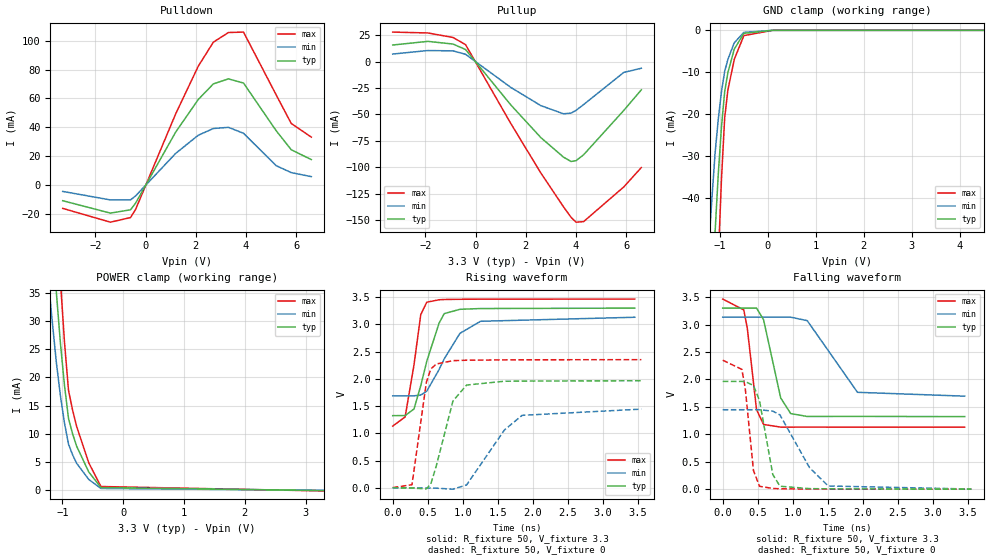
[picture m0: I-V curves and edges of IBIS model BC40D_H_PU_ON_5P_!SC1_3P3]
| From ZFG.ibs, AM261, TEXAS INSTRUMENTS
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[Model]   BC40D_H_PU_ON_5P_!SC1_3P3
Model_type   I/O
Polarity   Non-Inverting
Enable   Active-Low
Vinl =  0.8V
Vinh =  2V
Cref =  15pF
Rref =  100.0000M
Vref =  0V
Vmeas =  1.65
C_comp   2.157014p   1.964007p   2.198404p
|[Input load] weak_pu_on
|[Output drive] fast
|[supplytol] 5
|[temp] ind
[Model Spec]
Vinl   0.8V   0.8V   0.8V
Vinh   2V   2V   2V
[Temperature Range]   25   125   -40
[Voltage Range]   3.3   3.135   3.465
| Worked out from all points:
|   slope of the pulldown table from 0 to 0.495 V, typ, clamps not added: 31.8 ohm
|   slope of the pullup table from 0 to 0.495 V, typ, clamps not added: 33.3 ohm
|   GND clamp passes 1 mA (typ) near -0.52 V on its own axis
|   POWER clamp passes 1 mA (typ) near -0.43 V on its own axis
|   rising waveform, R_fixture 50, V_fixture 3.3: 20-80 % time 258ps typ, 377ps min, 156ps max; typ from 1.32 V to 3.3 V
|   rising waveform, R_fixture 50, V_fixture 0: 20-80 % time 233ps typ, 458ps min, 142ps max; typ from 0 V to 1.97 V
|   falling waveform, R_fixture 50, V_fixture 3.3: 20-80 % time 199ps typ, 410ps min, 121ps max; typ from 3.3 V to 1.32 V
|   falling waveform, R_fixture 50, V_fixture 0: 20-80 % time 162ps typ, 365ps min, 108ps max; typ from 1.96 V to 0.003 V
| Nom Voltages:
|   VDD=1.1, VDDS=3.3, VDDS18=1.8, ESD_BIASFET=0, VSS=0, VSSS=0
| Min Voltages:
|   VDD=1.045, VDDS=3.135, VDDS18=1.71, ESD_BIASFET=0, VSS=0, VSSS=0
| Max Voltages:
|   VDD=1.16, VDDS=3.465, VDDS18=1.89, ESD_BIASFET=0, VSS=0, VSSS=0
[POWER_clamp]
|   voltage   I(typ)   I(min)   I(max)
-3.3V     446.9mA    437.1mA    604mA
-1.233V   56.55mA    37.5mA     80.28mA
-1.167V   45.63mA    29.89mA    65.07mA
-1.1V     35.1mA     22.65mA    50.26mA
-1.033V   26.08mA    16.75mA    37.2mA
-966.7mV  18.62mA    11.92mA    26.34mA
-900mV    12.7mA     8.144mA    17.7mA
-833.3mV  10mA       6.261mA    14.22mA
-766.7mV  7.795mA    4.75mA     11.31mA
-566.7mV  3.199mA    1.871mA    4.824mA
-366.7mV  433.5uA    268.9uA    617.1uA
3.3V      -100.3uA   -54.66uA   -173.1uA
[Pulldown]
|   voltage   I(typ)   I(min)   I(max)
-3.3V     -10.92mA   -4.469mA   -16.24mA
-1.4V     -19.52mA   -10.37mA   -25.81mA
-600mV    -17.22mA   -10.34mA   -22.6mA
-400mV    -12.67mA   -7.623mA   -17.05mA
1.2V      36.7mA     21.92mA    49.35mA
2.1V      59.3mA     34.49mA    82.4mA
2.7V      70.09mA    39.15mA    99.03mA
3.3V      73.56mA    39.95mA    105.7mA
3.9V      70.66mA    35.84mA    106mA
5.2V      37.64mA    13.39mA    62.46mA
5.8V      24.43mA    8.578mA    42.66mA
6.6V      17.6mA     5.765mA    33.17mA
[Pullup]
|   voltage   I(typ)   I(min)   I(max)
-3.3V     15.77mA    7.22mA     28.03mA
-1.9V     19.23mA    10.53mA    27.2mA
-900mV    16.69mA    10.25mA    22.94mA
-400mV    11.53mA    6.969mA    16.15mA
1.4V      -40.96mA   -24.37mA   -58.54mA
2.6V      -72.01mA   -41.71mA   -105.6mA
3.5V      -90.51mA   -49.41mA   -137.6mA
3.8V      -94.64mA   -48.83mA   -147.5mA
4V        -93.89mA   -46.21mA   -152.2mA
4.3V      -88.33mA   -40.72mA   -151.7mA
5.9V      -46.29mA   -10.2mA    -118.8mA
6.6V      -26.71mA   -6.269mA   -100.4mA
[GND_clamp]
|   voltage   I(typ)   I(min)   I(max)
-3.3V     -787.2mA   -627.7mA   -1.235A
-1.233V   -85.67mA   -52.14mA   -138.8mA
-1.167V   -66.48mA   -40.37mA   -107.8mA
-1.1V     -48.26mA   -29.38mA   -78.01mA
-1.033V   -34.3mA    -21.2mA    -54.61mA
-966.7mV  -23.1mA    -14.68mA   -35.59mA
-900mV    -14.66mA   -9.807mA   -20.94mA
-833.3mV  -10.12mA   -6.96mA    -14.29mA
-700mV    -4.501mA   -2.971mA   -6.963mA
-500mV    -717.7uA   -493.4uA   -1.261mA
100mV     0A         0A         0A
6.6V      0A         0A         0A
[Ramp]
| variable   typ   min   max
dV/dt_f  1.1950009/0.20080853n 0.88975764/0.42406791n  1.4061698/0.12174193n
dV/dt_r  1.1920104/0.23568046n 0.88882206/0.46966013n  1.4196578/0.14317133n
R_load = 50
[Rising Waveform]
R_fixture = 50
V_fixture = 3.3
V_fixture_min = 3.135
V_fixture_max = 3.465
|   time   V(typ)   V(min)   V(max)
0s        1.324V     1.688V     1.132V
177.2ps   1.325V     1.688V     1.301V
303.7ps   1.447V     1.688V     2.256V
400.3ps   1.875V     1.703V     3.18V
485.8ps   2.322V     1.773V     3.407V
661.9ps   3.024V     2.171V     3.452V
735.5ps   3.198V     2.369V     3.457V
959.3ps   3.277V     2.836V     3.461V
1.253ns   3.291V     3.057V     3.463V
3.453ns   3.299V     3.131V     3.465V
[Rising Waveform]
R_fixture = 50
V_fixture = 0
V_fixture_min = 0
V_fixture_max = 0
|   time   V(typ)   V(min)   V(max)
0s        0V         0V         3.507mV
274.9ps   -4.733mV   0V         55.55mV
480.1ps   -20.97mV   -3.534mV   1.937V
543.7ps   69.38mV    -5.301mV   2.181V
622.4ps   404.7mV    -7.595mV   2.273V
859ps     1.592V     -25.75mV   2.334V
1.054ns   1.886V     51.53mV    2.342V
1.594ns   1.956V     1.061V     2.348V
1.846ns   1.959V     1.33V      2.35V
3.547ns   1.965V     1.444V     2.352V
[Falling Waveform]
R_fixture = 50
V_fixture = 3.3
V_fixture_min = 3.135
V_fixture_max = 3.465
|   time   V(typ)   V(min)   V(max)
0s        3.3V       3.134V     3.464V
301ps     3.3V       3.134V     3.266V
351.3ps   3.3V       3.134V     2.93V
482.7ps   3.3V       3.134V     1.45V
582.8ps   3.088V     3.134V     1.181V
827.6ps   1.663V     3.134V     1.132V
969.8ps   1.379V     3.134V     1.132V
1.206ns   1.326V     3.071V     1.133V
1.923ns   1.327V     1.766V     1.131V
3.453ns   1.324V     1.696V     1.131V
[Falling Waveform]
R_fixture = 50
V_fixture = 0
V_fixture_min = 0
V_fixture_max = 0
|   time   V(typ)   V(min)   V(max)
0s        1.964V     1.449V     2.351V
273.2ps   1.964V     1.449V     2.184V
322.1ps   1.961V     1.449V     1.833V
438.5ps   1.891V     1.449V     343.6mV
525.2ps   1.614V     1.449V     54.57mV
714.7ps   268.2mV    1.423V     15.15mV
817.3ps   55.88mV    1.353V     9.958mV
1.24ns    12.36mV    391.8mV    4.301mV
1.506ns   8.553mV    60.15mV    3.207mV
3.547ns   2.504mV    4.605mV    2.797mV
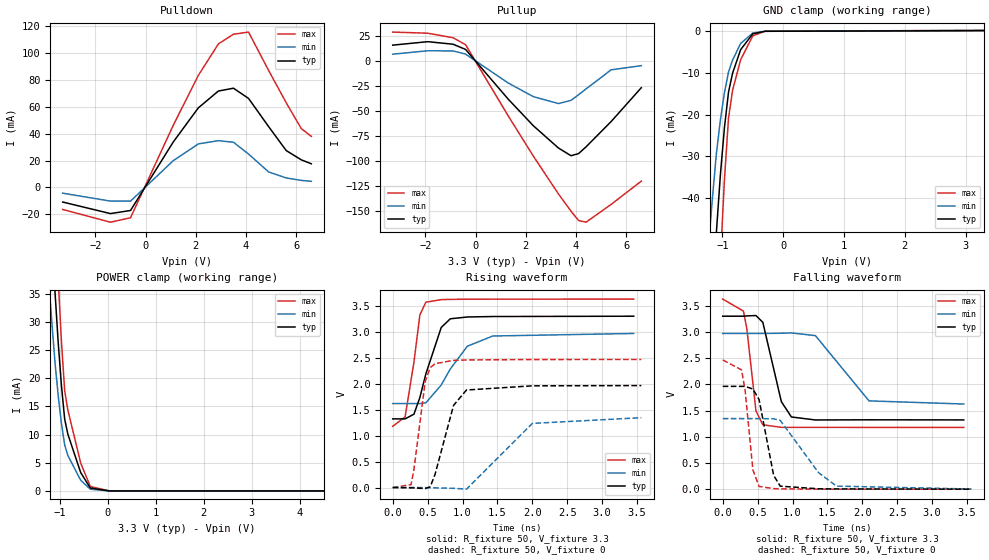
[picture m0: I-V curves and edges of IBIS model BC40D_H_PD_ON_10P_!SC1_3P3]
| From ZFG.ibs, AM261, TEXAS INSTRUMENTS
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[Model]   BC40D_H_PD_ON_10P_!SC1_3P3
Model_type   I/O
Polarity   Non-Inverting
Enable   Active-Low
Vinl =  0.8V
Vinh =  2V
Cref =  15pF
Rref =  100.0000M
Vref =  0V
Vmeas =  1.65
C_comp   2.157014p   1.997104p   2.250886p
|[Input load] weak_pd_on
|[Output drive] fast
|[supplytol] 10
|[temp] ind
[Model Spec]
Vinl   0.8V   0.8V   0.8V
Vinh   2V   2V   2V
[Temperature Range]   25   125   -40
[Voltage Range]   3.3   2.97   3.63
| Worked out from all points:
|   slope of the pulldown table from 0 to 0.495 V, typ, clamps not added: 31.8 ohm
|   slope of the pullup table from 0 to 0.495 V, typ, clamps not added: 33.3 ohm
|   GND clamp passes 1 mA (typ) near -0.52 V on its own axis
|   POWER clamp passes 1 mA (typ) near -0.42 V on its own axis
|   rising waveform, R_fixture 50, V_fixture 3.3: 20-80 % time 258ps typ, 391ps min, 146ps max; typ from 1.32 V to 3.3 V
|   rising waveform, R_fixture 50, V_fixture 0: 20-80 % time 233ps typ, 479ps min, 138ps max; typ from 0 V to 1.96 V
|   falling waveform, R_fixture 50, V_fixture 3.3: 20-80 % time 199ps typ, 427ps min, 119ps max; typ from 3.3 V to 1.32 V
|   falling waveform, R_fixture 50, V_fixture 0: 20-80 % time 162ps typ, 386ps min, 107ps max; typ from 1.96 V to 0 V
| Nom Voltages:
|   VDD=1.1001, VDDS=3.3, VDDS18=1.8, ESD_BIASFET=0, VSS=0, VSSS=0
| Min Voltages:
|   VDD=0.99, VDDS=2.97, VDDS18=1.62, ESD_BIASFET=0, VSS=0, VSSS=0
| Max Voltages:
|   VDD=1.21, VDDS=3.63, VDDS18=1.98, ESD_BIASFET=0, VSS=0, VSSS=0
[POWER_clamp]
|   voltage   I(typ)   I(min)   I(max)
-3.3V     446.9mA    419.5mA    603.9mA
-1.233V   56.59mA    37.53mA    80.37mA
-1.167V   45.68mA    29.91mA    65.17mA
-1.1V     35.14mA    22.68mA    50.36mA
-1.033V   26.13mA    16.78mA    37.31mA
-966.7mV  18.67mA    11.95mA    26.46mA
-900mV    12.76mA    8.172mA    17.82mA
-833.3mV  10.07mA    6.29mA     14.35mA
-566.7mV  3.276mA    1.904mA    4.983mA
-366.7mV  519.9uA    307.2uA    792.3uA
33.33mV   0A         0A         0A
6.6V      0A         0A         0A
[Pulldown]
|   voltage   I(typ)   I(min)   I(max)
-3.3V     -10.92mA   -4.307mA   -16.45mA
-1.4V     -19.52mA   -10.22mA   -25.94mA
-600mV    -17.22mA   -10.25mA   -22.66mA
1.1V      33.8mA     19.88mA    46.22mA
2.1V      59.3mA     32.44mA    83.48mA
2.9V      71.86mA    34.84mA    107mA
3.5V      73.95mA    33.66mA    114.2mA
4.1V      66.34mA    24.89mA    115.8mA
4.9V      45.33mA    11.53mA    87.2mA
5.6V      27.47mA    7.046mA    63.1mA
6.2V      20.56mA    5.221mA    43.87mA
6.6V      17.6mA     4.555mA    38.05mA
[Pullup]
|   voltage   I(typ)   I(min)   I(max)
-3.3V     15.77mA    6.741mA    28.8mA
-1.9V     19.23mA    10.15mA    27.67mA
-900mV    16.69mA    10.02mA    23.17mA
-400mV    11.53mA    6.853mA    16.25mA
1.3V      -38.16mA   -22.04mA   -54.89mA
2.3V      -64.7mA    -35.66mA   -95.04mA
3.3V      -86.93mA   -42.57mA   -132.8mA
3.8V      -94.64mA   -39.36mA   -150mA
4.1V      -92.53mA   -33.79mA   -159.3mA
4.4V      -85.77mA   -27.94mA   -161mA
5.4V      -60.46mA   -8.849mA   -143.2mA
6.6V      -26.71mA   -4.741mA   -120mA
[GND_clamp]
|   voltage   I(typ)   I(min)   I(max)
-3.3V     -787.2mA   -607.8mA   -1.235A
-1.233V   -85.66mA   -52.14mA   -138.8mA
-1.167V   -66.47mA   -40.37mA   -107.7mA
-1.1V     -48.25mA   -29.37mA   -77.99mA
-1.033V   -34.28mA   -21.19mA   -54.56mA
-966.7mV  -23.07mA   -14.67mA   -35.51mA
-900mV    -14.62mA   -9.792mA   -20.84mA
-833.3mV  -10.07mA   -6.938mA   -14.17mA
-700mV    -4.435mA   -2.939mA   -6.836mA
-500mV    -641.2uA   -454.5uA   -1.12mA
-300mV    -31.62uA   -32.73uA   -44.27uA
3.3V      108.6uA    159.4uA    198.5uA
[Ramp]
| variable   typ   min   max
dV/dt_f  1.1954816/0.20074978n 0.83576296/0.44363752n  1.4751037/0.11965581n
dV/dt_r  1.1916349/0.23568191n 0.82814892/0.49061137n  1.4892937/0.13872759n
R_load = 50
[Rising Waveform]
R_fixture = 50
V_fixture = 3.3
V_fixture_min = 2.97
V_fixture_max = 3.63
|   time   V(typ)   V(min)   V(max)
0s        1.321V     1.616V     1.179V
177.6ps   1.321V     1.616V     1.358V
303.9ps   1.411V     1.616V     2.409V
389.3ps   1.733V     1.616V     3.322V
475.1ps   2.187V     1.631V     3.566V
695.1ps   3.08V      1.973V     3.616V
824.7ps   3.247V     2.281V     3.621V
1.069ns   3.282V     2.719V     3.624V
1.434ns   3.291V     2.916V     3.625V
3.453ns   3.297V     2.965V     3.627V
[Rising Waveform]
R_fixture = 50
V_fixture = 0
V_fixture_min = 0
V_fixture_max = 0
|   time   V(typ)   V(min)   V(max)
0s        0V         0V         0V
263ps     -5.429mV   0V         55.93mV
302.5ps   -7.292mV   0V         330.3mV
465.3ps   -20.65mV   -2.403mV   2.039V
538ps     15.37mV    -3.759mV   2.309V
607.8ps   257.9mV    -5.571mV   2.384V
871.4ps   1.58V      -15.22mV   2.447V
1.057ns   1.877V     -31.71mV   2.455V
2.001ns   1.957V     1.234V     2.463V
3.562ns   1.962V     1.344V     2.465V
[Falling Waveform]
R_fixture = 50
V_fixture = 3.3
V_fixture_min = 2.97
V_fixture_max = 3.63
|   time   V(typ)   V(min)   V(max)
0s        3.299V     2.97V      3.626V
296.4ps   3.299V     2.97V      3.397V
344.8ps   3.305V     2.97V      3.071V
476.3ps   3.312V     2.97V      1.493V
574.8ps   3.182V     2.97V      1.228V
840.1ps   1.67V      2.974V     1.179V
984ps     1.377V     2.98V      1.179V
1.328ns   1.32V      2.929V     1.179V
2.096ns   1.323V     1.684V     1.178V
3.453ns   1.321V     1.624V     1.178V
[Falling Waveform]
R_fixture = 50
V_fixture = 0
V_fixture_min = 0
V_fixture_max = 0
|   time   V(typ)   V(min)   V(max)
0s        1.961V     1.346V     2.465V
269.2ps   1.961V     1.346V     2.276V
320ps     1.96V      1.346V     1.899V
432.6ps   1.911V     1.346V     366.2mV
521.1ps   1.709V     1.346V     52.16mV
729.8ps   262.9mV    1.343V     10.73mV
824.7ps   56.8mV     1.312V     6.105mV
1.374ns   6.947mV    314mV      0V
1.63ns    4.837mV    58.06mV    0V
3.562ns   0V         2.766mV    0V
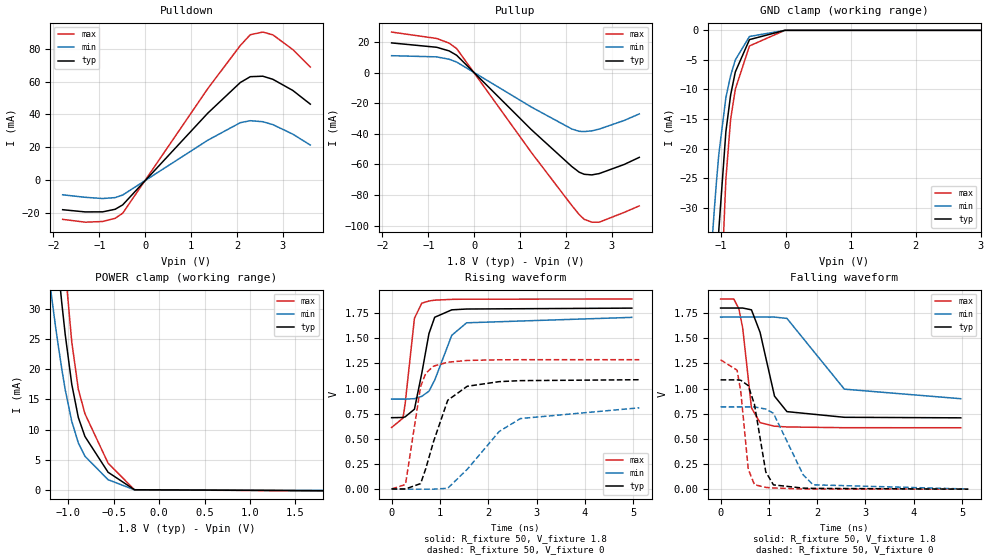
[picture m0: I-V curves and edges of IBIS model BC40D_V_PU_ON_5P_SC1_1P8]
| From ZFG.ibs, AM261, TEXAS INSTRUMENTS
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[Model]   BC40D_V_PU_ON_5P_SC1_1P8
Model_type   I/O
Polarity   Non-Inverting
Enable   Active-Low
Vinl =  0.63
Vinh =  1.17
Cref =  15pF
Rref =  100.0000M
Vref =  0V
Vmeas =  0.9
C_comp   2.233931p   2.204415p   2.290246p
|[Input load] weak_pu_on
|[Output drive] slow
|[supplytol] 5
|[temp] ind
[Model Spec]
Vinl   0.63   0.5985   0.6615
Vinh   1.17   1.1115   1.2285
[Temperature Range]   25   125   -40
[Voltage Range]   1.8   1.71   1.89
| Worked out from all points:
|   slope of the pulldown table from 0 to 0.27 V, typ, clamps not added: 32.2 ohm
|   slope of the pullup table from 0 to 0.27 V, typ, clamps not added: 32.6 ohm
|   GND clamp passes 1 mA (typ) near -0.52 V on its own axis
|   POWER clamp passes 1 mA (typ) near -0.44 V on its own axis
|   rising waveform, R_fixture 50, V_fixture 1.8: 20-80 % time 245ps typ, 395ps min, 168ps max; typ from 0.711 V to 1.8 V
|   rising waveform, R_fixture 50, V_fixture 0: 20-80 % time 428ps typ, 921ps min, 245ps max; typ from 0.002 V to 1.09 V
|   falling waveform, R_fixture 50, V_fixture 1.8: 20-80 % time 308ps typ, 718ps min, 171ps max; typ from 1.8 V to 0.71 V
|   falling waveform, R_fixture 50, V_fixture 0: 20-80 % time 226ps typ, 430ps min, 154ps max; typ from 1.09 V to 0.002 V
| Nom Voltages:
|   VDD=1.1, VDDS=1.8, VDDS18=1.8, ESD_BIASFET=0, VSS=0, VSSS=0
| Min Voltages:
|   VDD=1.045, VDDS=1.71, VDDS18=1.71, ESD_BIASFET=0, VSS=0, VSSS=0
| Max Voltages:
|   VDD=1.16, VDDS=1.89, VDDS18=1.89, ESD_BIASFET=0, VSS=0, VSSS=0
[POWER_clamp]
|   voltage   I(typ)   I(min)   I(max)
-1.8V     158.8mA    112.5mA    219.8mA
-1.255V   59.97mA    40.01mA    84.91mA
-1.145V   41.92mA    27.41mA    59.76mA
-1.109V   36.32mA    23.62mA    51.83mA
-1.073V   30.96mA    20.04mA    44.16mA
-1.036V   25.83mA    16.67mA    36.76mA
-963.6mV  17.54mA    11.39mA    24.56mA
-890.9mV  12.01mA    7.798mA    16.67mA
-818.2mV  8.875mA    5.598mA    12.64mA
-563.6mV  2.954mA    1.726mA    4.46mA
-272.7mV  55.97uA    39.54uA    57.56uA
1.8V      -99.94uA   -59.14uA   -145.1uA
[Pulldown]
|   voltage   I(typ)   I(min)   I(max)
-1.8V     -17.92mA   -8.85mA    -23.8mA
-1.309V   -19.26mA   -10.37mA   -25.51mA
-927.3mV  -19.22mA   -11.12mA   -25.08mA
-654.5mV  -17.65mA   -10.56mA   -23.13mA
-490.9mV  -14.97mA   -8.985mA   -20.05mA
1.364V    40.78mA    24.32mA    55.7mA
2.073V    59.4mA     35mA       81.9mA
2.291V    62.96mA    36.2mA     88.48mA
2.564V    63.25mA    35.58mA    90.07mA
2.782V    61.38mA    33.82mA    88.42mA
3.218V    54.59mA    28.02mA    79.45mA
3.6V      46.26mA    21.39mA    68.79mA
[Pullup]
-1.8V     19.42mA    11.07mA    26.5mA
-818.2mV  16.58mA    10.3mA     22.34mA
-545.5mV  14.19mA    8.748mA    19.29mA
-381.8mV  11.34mA    6.915mA    15.7mA
1.255V    -37.51mA   -22.64mA   -52.53mA
2.127V    -61.34mA   -36.82mA   -86.78mA
2.291V    -65.12mA   -38.38mA   -92.82mA
2.4V      -66.46mA   -38.53mA   -95.91mA
2.564V    -66.86mA   -38.08mA   -97.75mA
2.727V    -65.99mA   -36.9mA    -97.78mA
3.273V    -60.01mA   -31.26mA   -91.34mA
3.6V      -55.4mA    -26.98mA   -87.12mA
[GND_clamp]
|   voltage   I(typ)   I(min)   I(max)
-1.8V     -270.2mA   -170.2mA   -430.1mA
-1.255V   -91.68mA   -55.92mA   -148.5mA
-1.145V   -59.94mA   -36.46mA   -97.14mA
-1.109V   -50.51mA   -30.84mA   -81.61mA
-1.073V   -41.77mA   -25.67mA   -67.13mA
-1.036V   -33.71mA   -20.95mA   -53.68mA
-927.3mV  -17.15mA   -11.38mA   -25.19mA
-854.5mV  -10.96mA   -7.663mA   -15.08mA
-781.8mV  -7.031mA   -5.001mA   -9.947mA
-563.6mV  -1.569mA   -1.041mA   -2.641mA
-18.18mV  0A         0A         0A
3.6V      0A         0A         0A
[Ramp]
| variable   typ   min   max
dV/dt_f 0.66095896/0.3106084n 0.49613312/0.73326127n 0.77259659/0.17250259n
dV/dt_r 0.65862655/0.43190461n 0.50230725/0.96092972n 0.77696157/0.24571965n
R_load = 50
[Rising Waveform]
R_fixture = 50
V_fixture = 1.8
V_fixture_min = 1.71
V_fixture_max = 1.89
|   time   V(typ)   V(min)   V(max)
0s        710.6mV    895.2mV    613.1mV
234.7ps   712.8mV    895.2mV    706mV
279.7ps   718.7mV    895.2mV    848.3mV
472.8ps   795.2mV    899.6mV    1.7V
625.3ps   1.154V     923mV      1.849V
773.2ps   1.547V     974.1mV    1.871V
891.9ps   1.709V     1.084V     1.879V
1.246ns   1.783V     1.53V      1.887V
1.553ns   1.791V     1.654V     1.889V
4.974ns   1.8V       1.708V     1.89V
[Rising Waveform]
R_fixture = 50
V_fixture = 0
V_fixture_min = 0
V_fixture_max = 0
|   time   V(typ)   V(min)   V(max)
0s        2.021mV    0V         2.349mV
286.7ps   2.021mV    0V         46.67mV
600.6ps   55.49mV    0V         1.02V
705.3ps   201.5mV    0V         1.151V
868.1ps   473.5mV    0V         1.223V
1.162ns   884.2mV    8.941mV    1.262V
1.566ns   1.023V     197.8mV    1.28V
2.228ns   1.069V     573.6mV    1.286V
2.667ns   1.079V     702.1mV    1.287V
5.128ns   1.088V     808.9mV    1.287V
[Falling Waveform]
R_fixture = 50
V_fixture = 1.8
V_fixture_min = 1.71
V_fixture_max = 1.89
|   time   V(typ)   V(min)   V(max)
0s        1.8V       1.71V      1.889V
275ps     1.8V       1.71V      1.889V
378.3ps   1.8V       1.71V      1.793V
458.3ps   1.8V       1.71V      1.601V
639.6ps   1.782V     1.71V      809mV
817.4ps   1.559V     1.71V      662.6mV
1.117ns   924.9mV    1.71V      627.2mV
1.374ns   771.8mV    1.697V     619.7mV
2.563ns   715.4mV    994.7mV    612.1mV
4.974ns   710.1mV    900mV      611.7mV
[Falling Waveform]
R_fixture = 50
V_fixture = 0
V_fixture_min = 0
V_fixture_max = 0
|   time   V(typ)   V(min)   V(max)
0s        1.087V     818.9mV    1.286V
342.4ps   1.087V     818.9mV    1.183V
418.5ps   1.083V     818.9mV    970.8mV
572.8ps   1.03V      818.9mV    201.5mV
701.2ps   844.1mV    818.9mV    46.7mV
936.2ps   172.9mV    797.1mV    19.49mV
1.095ns   44.58mV    755.1mV    13.55mV
1.708ns   12.56mV    145.8mV    3.939mV
1.914ns   10.01mV    45.38mV    3.232mV
5.128ns   2.074mV    3.413mV    2.43mV
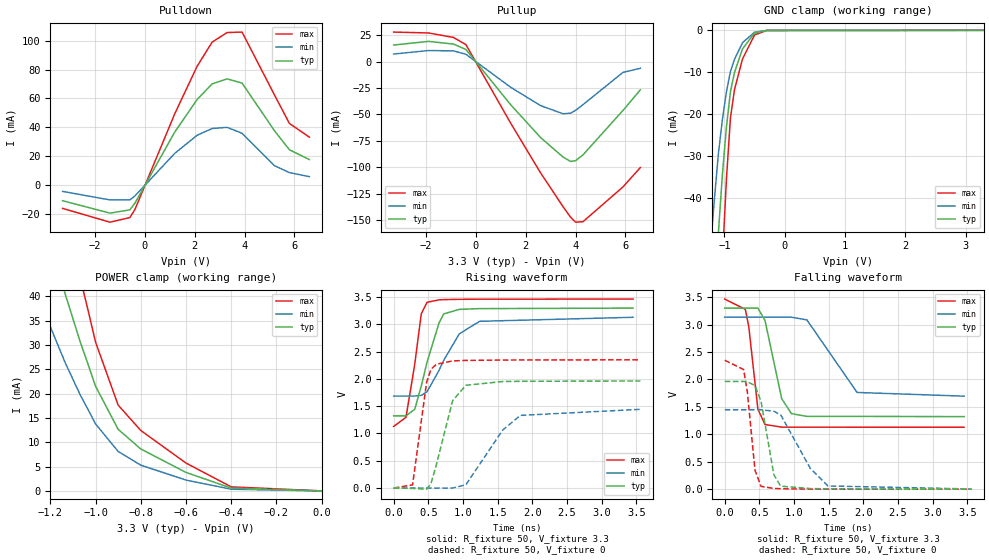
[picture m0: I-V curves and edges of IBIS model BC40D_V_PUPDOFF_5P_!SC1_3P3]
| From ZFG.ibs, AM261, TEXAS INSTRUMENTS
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[Model]   BC40D_V_PUPDOFF_5P_!SC1_3P3
Model_type   I/O
Polarity   Non-Inverting
Enable   Active-Low
Vinl =  0.8V
Vinh =  2V
Cref =  15pF
Rref =  100.0000M
Vref =  0V
Vmeas =  1.65
C_comp   2.059994p   1.862014p   2.067327p
|[Input load] weak_pupdoff
|[Output drive] fast
|[supplytol] 5
|[temp] ind
[Model Spec]
Vinl   0.8V   0.8V   0.8V
Vinh   2V   2V   2V
[Temperature Range]   25   125   -40
[Voltage Range]   3.3   3.135   3.465
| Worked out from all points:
|   slope of the pulldown table from 0 to 0.495 V, typ, clamps not added: 31.8 ohm
|   slope of the pullup table from 0 to 0.495 V, typ, clamps not added: 33.3 ohm
|   GND clamp passes 1 mA (typ) near -0.53 V on its own axis
|   POWER clamp passes 1 mA (typ) near -0.43 V on its own axis
|   rising waveform, R_fixture 50, V_fixture 3.3: 20-80 % time 251ps typ, 371ps min, 151ps max; typ from 1.32 V to 3.3 V
|   rising waveform, R_fixture 50, V_fixture 0: 20-80 % time 232ps typ, 456ps min, 141ps max; typ from 0 V to 1.96 V
|   falling waveform, R_fixture 50, V_fixture 3.3: 20-80 % time 196ps typ, 407ps min, 120ps max; typ from 3.3 V to 1.32 V
|   falling waveform, R_fixture 50, V_fixture 0: 20-80 % time 159ps typ, 360ps min, 107ps max; typ from 1.96 V to 0 V
| Nom Voltages:
|   VDD=1.1, VDDS=3.3, VDDS18=1.8, ESD_BIASFET=0, VSS=0, VSSS=0
| Min Voltages:
|   VDD=1.045, VDDS=3.135, VDDS18=1.71, ESD_BIASFET=0, VSS=0, VSSS=0
| Max Voltages:
|   VDD=1.16, VDDS=3.465, VDDS18=1.89, ESD_BIASFET=0, VSS=0, VSSS=0
[POWER_clamp]
|   voltage   I(typ)   I(min)   I(max)
-3.3V     446.9mA    437.1mA    604mA
-1.267V   62.17mA    41.49mA    88.04mA
-1.233V   56.52mA    37.49mA    80.24mA
-1.133V   40.34mA    26.26mA    57.63mA
-1.067V   30.56mA    19.69mA    43.69mA
-1.033V   26.05mA    16.74mA    37.16mA
-1V       21.55mA    13.79mA    30.63mA
-900mV    12.68mA    8.13mA     17.66mA
-800mV    8.63mA     5.305mA    12.44mA
-600mV    3.813mA    2.231mA    5.735mA
-400mV    580.7uA    357.4uA    841.8uA
0V        4.589uA    2.331uA    8.159uA
[Pulldown]
|   voltage   I(typ)   I(min)   I(max)
-3.3V     -10.92mA   -4.469mA   -16.24mA
-1.4V     -19.52mA   -10.37mA   -25.81mA
-600mV    -17.22mA   -10.34mA   -22.6mA
-400mV    -12.67mA   -7.623mA   -17.05mA
1.2V      36.7mA     21.92mA    49.35mA
2.1V      59.3mA     34.49mA    82.4mA
2.7V      70.09mA    39.15mA    99.03mA
3.3V      73.56mA    39.95mA    105.7mA
3.9V      70.66mA    35.84mA    106mA
5.2V      37.64mA    13.39mA    62.46mA
5.8V      24.43mA    8.578mA    42.66mA
6.6V      17.6mA     5.765mA    33.17mA
[Pullup]
|   voltage   I(typ)   I(min)   I(max)
-3.3V     15.77mA    7.22mA     28.03mA
-1.9V     19.23mA    10.53mA    27.2mA
-900mV    16.69mA    10.25mA    22.94mA
-400mV    11.53mA    6.969mA    16.15mA
1.4V      -40.96mA   -24.37mA   -58.54mA
2.6V      -72.01mA   -41.71mA   -105.6mA
3.5V      -90.51mA   -49.41mA   -137.6mA
3.8V      -94.64mA   -48.83mA   -147.5mA
4V        -93.88mA   -46.2mA    -152.2mA
4.3V      -88.33mA   -40.72mA   -151.7mA
5.9V      -46.29mA   -10.2mA    -118.8mA
6.6V      -26.71mA   -6.269mA   -100.4mA
[GND_clamp]
|   voltage   I(typ)   I(min)   I(max)
-3.3V     -787.2mA   -627.7mA   -1.235A
-1.233V   -85.66mA   -52.14mA   -138.8mA
-1.167V   -66.47mA   -40.37mA   -107.7mA
-1.1V     -48.25mA   -29.37mA   -77.98mA
-1.033V   -34.27mA   -21.19mA   -54.56mA
-966.7mV  -23.06mA   -14.66mA   -35.5mA
-900mV    -14.61mA   -9.789mA   -20.83mA
-833.3mV  -10.05mA   -6.934mA   -14.15mA
-700mV    -4.416mA   -2.931mA   -6.81mA
-500mV    -621.6uA   -443.6uA   -1.094mA
-300mV    -17.13uA   -24.35uA   -23.51uA
3.3V      4.589uA    5.188uA    6.318uA
[Ramp]
| variable   typ   min   max
dV/dt_f  1.1959432/0.19778326n 0.88997478/0.42010629n  1.4076426/0.12045204n
dV/dt_r  1.1917501/0.23458044n 0.88925157/0.46804062n  1.4206668/0.14157829n
R_load = 50
[Rising Waveform]
R_fixture = 50
V_fixture = 3.3
V_fixture_min = 3.135
V_fixture_max = 3.465
|   time   V(typ)   V(min)   V(max)
0s        1.323V     1.687V     1.129V
178.2ps   1.324V     1.687V     1.297V
304.7ps   1.446V     1.687V     2.276V
398.7ps   1.871V     1.7V       3.195V
481.7ps   2.309V     1.765V     3.406V
653.8ps   3.025V     2.155V     3.45V
722.6ps   3.193V     2.343V     3.455V
946.6ps   3.276V     2.827V     3.46V
1.239ns   3.29V      3.057V     3.463V
3.453ns   3.299V     3.131V     3.465V
[Rising Waveform]
R_fixture = 50
V_fixture = 0
V_fixture_min = 0
V_fixture_max = 0
|   time   V(typ)   V(min)   V(max)
0s        0V         0V         0V
272.8ps   -6.681mV   0V         57.86mV
474.8ps   -20.71mV   0V         1.934V
537.3ps   78.73mV    0V         2.176V
615.7ps   426mV      0V         2.269V
850ps     1.601V     0V         2.331V
1.042ns   1.884V     59.9mV     2.34V
1.571ns   1.953V     1.06V      2.347V
1.827ns   1.957V     1.332V     2.348V
3.559ns   1.963V     1.443V     2.351V
[Falling Waveform]
R_fixture = 50
V_fixture = 3.3
V_fixture_min = 3.135
V_fixture_max = 3.465
|   time   V(typ)   V(min)   V(max)
0s        3.299V     3.134V     3.464V
297.1ps   3.299V     3.134V     3.277V
347.5ps   3.299V     3.134V     2.96V
479.2ps   3.299V     3.134V     1.457V
581.1ps   3.075V     3.134V     1.179V
822.1ps   1.65V      3.134V     1.13V
962ps     1.377V     3.134V     1.13V
1.186ns   1.326V     3.084V     1.13V
1.91ns    1.326V     1.762V     1.129V
3.453ns   1.322V     1.695V     1.129V
[Falling Waveform]
R_fixture = 50
V_fixture = 0
V_fixture_min = 0
V_fixture_max = 0
|   time   V(typ)   V(min)   V(max)
0s        1.963V     1.448V     2.35V
273.4ps   1.963V     1.448V     2.179V
326.7ps   1.958V     1.448V     1.774V
436.6ps   1.889V     1.448V     346mV
524.2ps   1.602V     1.448V     51.4mV
709.5ps   262.9mV    1.42V      13.06mV
807.3ps   55.33mV    1.355V     7.941mV
1.237ns   10.47mV    375.2mV    0V
1.49ns    6.698mV    58.45mV    0V
3.559ns   0V         3.299mV    0V
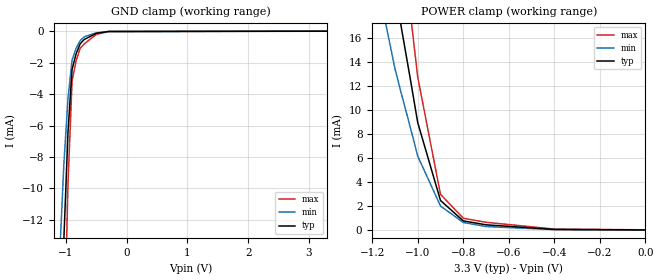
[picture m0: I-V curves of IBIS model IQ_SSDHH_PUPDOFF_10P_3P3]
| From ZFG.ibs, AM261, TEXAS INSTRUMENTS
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[Model]   IQ_SSDHH_PUPDOFF_10P_3P3
Model_type   Input
Polarity   Non-Inverting
Vinl =  0.8V
Vinh =  2V
C_comp   1.115166p   0.9908539p   1.211879p
|[Input load] weak_pupdoff
|[supplytol] 10
|[temp] ind
[Model Spec]
Vinl   0.8V   0.8V   0.8V
Vinh   2V   2V   2V
[Temperature Range]   25   125   -40
[Voltage Range]   3.3   2.97   3.63
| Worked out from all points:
|   GND clamp passes 1 mA (typ) near -0.79 V on its own axis
|   POWER clamp passes 1 mA (typ) near -0.81 V on its own axis
| Nom Voltages:
|   VDD=1.1001, VDDS=3.3, VDDS18=1.8, BUS_VSSS=0, ESD_BIASFET=0, VSS=0
| Min Voltages:
|   VDD=0.99, VDDS=2.97, VDDS18=1.62, BUS_VSSS=0, ESD_BIASFET=0, VSS=0
| Max Voltages:
|   VDD=1.21, VDDS=3.63, VDDS18=1.98, BUS_VSSS=0, ESD_BIASFET=0, VSS=0
[POWER_clamp]
|   voltage   I(typ)   I(min)   I(max)
-3.3V     372.1mA    370.8mA    506.4mA
-1.167V   28.96mA    19.64mA    41.7mA
-1.133V   24.52mA    16.55mA    35.4mA
-1.1V     20.07mA    13.47mA    29.11mA
-1.067V   16.37mA    11.04mA    23.67mA
-1.033V   12.67mA    8.603mA    18.22mA
-1V       8.974mA    6.17mA     12.78mA
-900mV    2.467mA    2.004mA    2.98mA
-800mV    758.8uA    626.3uA    979uA
-700mV    431.9uA    286.3uA    641.7uA
-400mV    45.5uA     27.22uA    74.37uA
0V        2.776uA    952.1nA    13.43uA
[GND_clamp]
|   voltage   I(typ)   I(min)   I(max)
-3.3V     -586.5mA   -502.8mA   -870.7mA
-1.1V     -22.35mA   -13.96mA   -35.17mA
-1.033V   -13.07mA   -8.329mA   -20.39mA
-966.7mV  -6.432mA   -4.287mA   -9.727mA
-900mV    -2.433mA   -1.832mA   -3.194mA
-833.3mV  -1.436mA   -1.091mA   -1.89mA
-766.7mV  -800.1uA   -598uA     -1.092mA
-700mV    -525.1uA   -353.9uA   -800.1uA
-500mV    -130.5uA   -96.02uA   -196.5uA
-300mV    -12.45uA   -18.73uA   -15.71uA
3.3V      2.776uA    9.019uA    12.91uA
